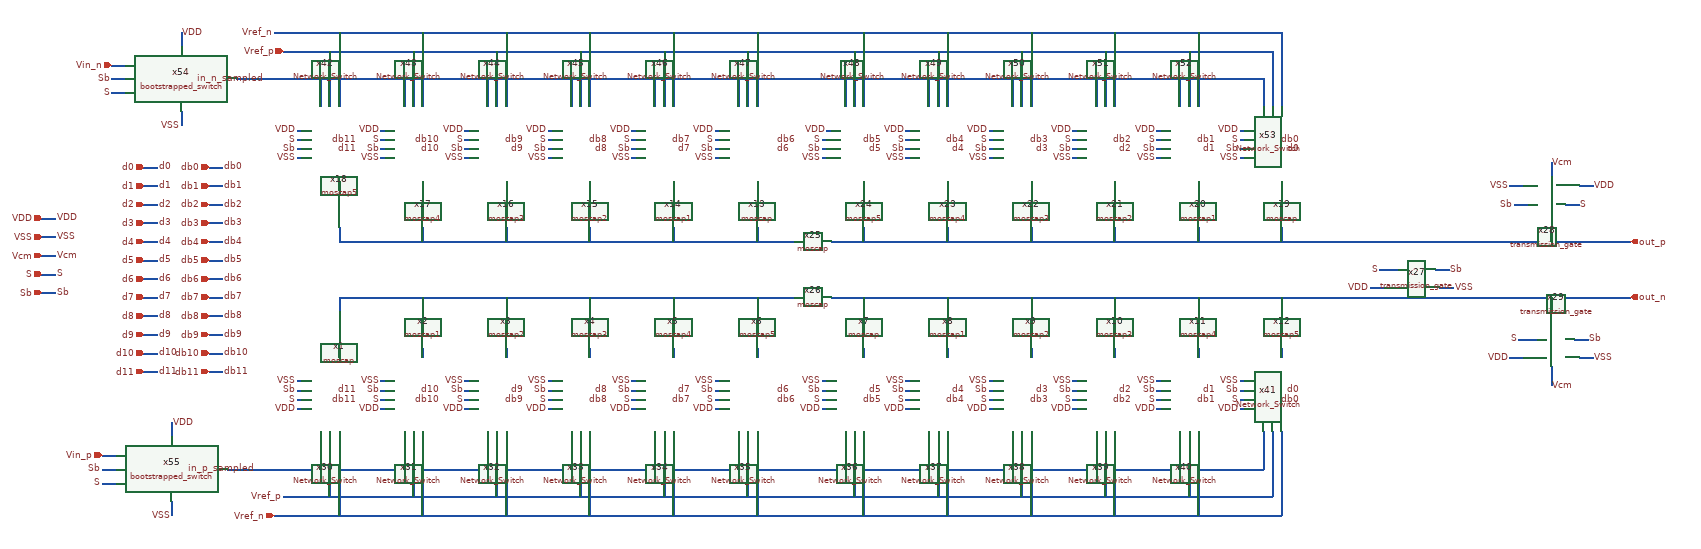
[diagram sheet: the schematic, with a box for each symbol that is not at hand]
v {xschem version=3.4.6 file_version=1.2}
G {}
K {}
V {}
S {}
E {}
N -460 -10 -460 20 {lab=#net1}
N -200 -10 520 -10 {lab=#net1}
N 600 -10 1320 -10 {lab=out_n}
N 1570 -10 1570 20 {lab=out_n}
N 1390 -10 1390 20 {lab=out_n}
N 1210 -10 1210 20 {lab=out_n}
N 1030 -10 1030 20 {lab=out_n}
N 850 -10 850 20 {lab=out_n}
N 670 -10 670 20 {lab=out_n}
N 440 -10 440 20 {lab=#net1}
N 260 -10 260 20 {lab=#net1}
N 80 -10 80 20 {lab=#net1}
N -100 -10 -100 20 {lab=#net1}
N -280 -10 -280 20 {lab=#net1}
N -460 -160 -460 -130 {lab=#net2}
N -200 -130 520 -130 {lab=#net2}
N 600 -130 1320 -130 {lab=out_p}
N 1570 -160 1570 -130 {lab=out_p}
N 1390 -160 1390 -130 {lab=out_p}
N 1210 -160 1210 -130 {lab=out_p}
N 1030 -160 1030 -130 {lab=out_p}
N 850 -160 850 -130 {lab=out_p}
N 670 -160 670 -130 {lab=out_p}
N 440 -160 440 -130 {lab=#net2}
N 260 -160 260 -130 {lab=#net2}
N 80 -160 80 -130 {lab=#net2}
N -100 -160 -100 -130 {lab=#net2}
N -280 -160 -280 -130 {lab=#net2}
N 2150 -300 2150 -270 {lab=Vcm}
N 1930 -130 2320 -130 {lab=out_p}
N 2150 -150 2150 -130 {lab=out_p}
N 1930 -10 2320 -10 {lab=out_n}
N 2150 -10 2150 20 {lab=out_n}
N 2180 -210 2210 -210 {lab=S}
N 2070 -210 2100 -210 {lab=Sb}
N 2060 -250 2090 -250 {lab=VSS}
N 2210 -250 2240 -250 {lab=VDD}
N 2200 80 2230 80 {lab=Sb}
N 2080 80 2120 80 {lab=S}
N 2150 140 2150 160 {lab=Vcm}
N 2210 120 2240 120 {lab=VSS}
N 2060 120 2090 120 {lab=VDD}
N 2150 160 2150 180 {lab=Vcm}
N -330 -10 -200 -10 {lab=#net1}
N -460 -10 -330 -10 {lab=#net1}
N 1320 -10 1780 -10 {lab=out_n}
N 1570 100 1570 120 {lab=#net3}
N 1390 100 1390 120 {lab=#net4}
N 1210 100 1210 120 {lab=#net5}
N 1030 100 1030 120 {lab=#net6}
N 850 100 850 120 {lab=#net7}
N 670 100 670 120 {lab=#net8}
N 1320 -130 1780 -130 {lab=out_p}
N -460 100 -460 120 {lab=#net9}
N -280 100 -280 120 {lab=#net10}
N -100 100 -100 120 {lab=#net11}
N 80 100 80 120 {lab=#net12}
N 440 100 440 120 {lab=#net13}
N 260 100 260 120 {lab=#net14}
N -460 -130 -200 -130 {lab=#net2}
N 1570 -260 1570 -240 {lab=#net15}
N 1390 -260 1390 -240 {lab=#net16}
N 1210 -260 1210 -240 {lab=#net17}
N 1030 -260 1030 -240 {lab=#net18}
N 850 -260 850 -240 {lab=#net19}
N 670 -260 670 -240 {lab=#net20}
N 440 -260 440 -240 {lab=#net21}
N 260 -260 260 -240 {lab=#net22}
N 80 -260 80 -240 {lab=#net23}
N -100 -260 -100 -240 {lab=#net24}
N -280 -260 -280 -240 {lab=#net25}
N -460 -260 -460 -240 {lab=#net26}
N -610 -480 -500 -480 {lab=in_n_sampled}
N -500 -480 -500 -420 {lab=in_n_sampled}
N -500 -480 1530 -480 {lab=in_n_sampled}
N 1530 -480 1530 -420 {lab=in_n_sampled}
N 1350 -480 1350 -420 {lab=in_n_sampled}
N 1170 -480 1170 -420 {lab=in_n_sampled}
N 990 -480 990 -420 {lab=in_n_sampled}
N 810 -480 810 -420 {lab=in_n_sampled}
N 630 -480 630 -420 {lab=in_n_sampled}
N -320 -480 -320 -420 {lab=in_n_sampled}
N -140 -480 -140 -420 {lab=in_n_sampled}
N 40 -480 40 -420 {lab=in_n_sampled}
N 220 -480 220 -420 {lab=in_n_sampled}
N 400 -480 400 -420 {lab=in_n_sampled}
N -600 360 1530 360 {lab=in_p_sampled}
N 1530 280 1530 360 {lab=in_p_sampled}
N 1350 280 1350 360 {lab=in_p_sampled}
N 1170 280 1170 360 {lab=in_p_sampled}
N 990 280 990 360 {lab=in_p_sampled}
N 810 280 810 360 {lab=in_p_sampled}
N 630 280 630 360 {lab=in_p_sampled}
N 400 280 400 360 {lab=in_p_sampled}
N 220 280 220 360 {lab=in_p_sampled}
N 40 280 40 360 {lab=in_p_sampled}
N -140 280 -140 360 {lab=in_p_sampled}
N -320 280 -320 360 {lab=in_p_sampled}
N -500 280 -500 360 {lab=in_p_sampled}
N -1100 -140 -1070 -140 {lab=VSS}
N -1100 -180 -1070 -180 {lab=VDD}
N -1100 -60 -1070 -60 {lab=S}
N -1100 -20 -1070 -20 {lab=Sb}
N -880 -170 -850 -170 {lab=d3}
N -740 -170 -710 -170 {lab=db3}
N -1100 -100 -1070 -100 {lab=Vcm}
N -800 -580 -800 -550 {lab=VDD}
N -820 260 -820 290 {lab=VDD}
N -550 -370 -540 -370 {lab=VDD}
N -370 -370 -360 -370 {lab=VDD}
N -190 -370 -180 -370 {lab=VDD}
N -10 -370 0 -370 {lab=VDD}
N 170 -370 180 -370 {lab=VDD}
N 350 -370 360 -370 {lab=VDD}
N 590 -370 600 -370 {lab=VDD}
N 760 -370 770 -370 {lab=VDD}
N 940 -370 950 -370 {lab=VDD}
N 1120 -370 1130 -370 {lab=VDD}
N 1300 -370 1310 -370 {lab=VDD}
N 1480 -370 1490 -370 {lab=VDD}
N -550 230 -540 230 {lab=VDD}
N -370 230 -360 230 {lab=VDD}
N -190 230 -180 230 {lab=VDD}
N -10 230 0 230 {lab=VDD}
N 170 230 180 230 {lab=VDD}
N 350 230 360 230 {lab=VDD}
N 580 230 590 230 {lab=VDD}
N 760 230 770 230 {lab=VDD}
N 940 230 950 230 {lab=VDD}
N 1300 230 1310 230 {lab=VDD}
N 1120 230 1130 230 {lab=VDD}
N 1480 230 1490 230 {lab=VDD}
N -800 -410 -800 -380 {lab=VSS}
N -820 430 -820 460 {lab=VSS}
N -550 170 -540 170 {lab=VSS}
N -370 170 -360 170 {lab=VSS}
N -190 170 -180 170 {lab=VSS}
N -10 170 0 170 {lab=VSS}
N 170 170 180 170 {lab=VSS}
N 350 170 360 170 {lab=VSS}
N 580 170 590 170 {lab=VSS}
N 760 170 770 170 {lab=VSS}
N 940 170 950 170 {lab=VSS}
N 1120 170 1130 170 {lab=VSS}
N 1300 170 1310 170 {lab=VSS}
N 1480 170 1490 170 {lab=VSS}
N -550 -310 -540 -310 {lab=VSS}
N -370 -310 -360 -310 {lab=VSS}
N -190 -310 -180 -310 {lab=VSS}
N -10 -310 0 -310 {lab=VSS}
N 170 -310 180 -310 {lab=VSS}
N 350 -310 360 -310 {lab=VSS}
N 580 -310 590 -310 {lab=VSS}
N 760 -310 770 -310 {lab=VSS}
N 940 -310 950 -310 {lab=VSS}
N 1120 -310 1130 -310 {lab=VSS}
N 1300 -310 1310 -310 {lab=VSS}
N 1480 -310 1490 -310 {lab=VSS}
N -680 -480 -610 -480 {lab=in_n_sampled}
N -700 360 -600 360 {lab=in_p_sampled}
N -580 -540 1550 -540 {lab=Vref_p}
N 1550 -540 1550 -420 {lab=Vref_p}
N 1570 -580 1570 -420 {lab=Vref_n}
N -600 -580 1570 -580 {lab=Vref_n}
N -480 -540 -480 -420 {lab=Vref_p}
N -460 -580 -460 -420 {lab=Vref_n}
N -300 -540 -300 -420 {lab=Vref_p}
N -280 -580 -280 -420 {lab=Vref_n}
N -120 -540 -120 -420 {lab=Vref_p}
N -100 -580 -100 -420 {lab=Vref_n}
N 60 -540 60 -420 {lab=Vref_p}
N 80 -580 80 -420 {lab=Vref_n}
N 240 -540 240 -420 {lab=Vref_p}
N 260 -580 260 -420 {lab=Vref_n}
N 420 -540 420 -420 {lab=Vref_p}
N 440 -580 440 -420 {lab=Vref_n}
N 650 -540 650 -420 {lab=Vref_p}
N 670 -580 670 -420 {lab=Vref_n}
N 830 -540 830 -420 {lab=Vref_p}
N 850 -580 850 -420 {lab=Vref_n}
N 1010 -540 1010 -420 {lab=Vref_p}
N 1030 -580 1030 -420 {lab=Vref_n}
N 1190 -540 1190 -420 {lab=Vref_p}
N 1210 -580 1210 -420 {lab=Vref_n}
N 1370 -540 1370 -420 {lab=Vref_p}
N 1390 -580 1390 -420 {lab=Vref_n}
N 1550 280 1550 420 {lab=Vref_p}
N -580 420 1550 420 {lab=Vref_p}
N 1570 280 1570 460 {lab=Vref_n}
N -600 460 1570 460 {lab=Vref_n}
N -480 280 -480 420 {lab=Vref_p}
N -460 280 -460 460 {lab=Vref_n}
N -300 280 -300 420 {lab=Vref_p}
N -280 280 -280 460 {lab=Vref_n}
N -120 280 -120 420 {lab=Vref_p}
N -100 280 -100 460 {lab=Vref_n}
N 60 280 60 420 {lab=Vref_p}
N 80 280 80 460 {lab=Vref_n}
N 240 280 240 420 {lab=Vref_p}
N 260 280 260 460 {lab=Vref_n}
N 420 280 420 420 {lab=Vref_p}
N 440 280 440 460 {lab=Vref_n}
N 650 280 650 420 {lab=Vref_p}
N 670 280 670 460 {lab=Vref_n}
N 830 280 830 420 {lab=Vref_p}
N 850 280 850 460 {lab=Vref_n}
N 1010 280 1010 420 {lab=Vref_p}
N 1030 280 1030 460 {lab=Vref_n}
N 1190 280 1190 420 {lab=Vref_p}
N 1210 280 1210 460 {lab=Vref_n}
N 1370 280 1370 420 {lab=Vref_p}
N 1390 280 1390 460 {lab=Vref_n}
N -880 -290 -850 -290 {lab=d0}
N -740 -290 -710 -290 {lab=db0}
N -880 -250 -850 -250 {lab=d1}
N -740 -250 -710 -250 {lab=db1}
N -880 -210 -850 -210 {lab=d2}
N -740 -210 -710 -210 {lab=db2}
N -880 -90 -850 -90 {lab=d5}
N -740 -90 -710 -90 {lab=db5}
N -880 -130 -850 -130 {lab=d4}
N -740 -130 -710 -130 {lab=db4}
N -880 -10 -850 -10 {lab=d7}
N -740 -10 -710 -10 {lab=db7}
N -880 -50 -850 -50 {lab=d6}
N -740 -50 -710 -50 {lab=db6}
N -880 70 -850 70 {lab=d9}
N -740 70 -710 70 {lab=db9}
N -880 30 -850 30 {lab=d8}
N -740 30 -710 30 {lab=db8}
N -880 150 -850 150 {lab=d11}
N -740 150 -710 150 {lab=db11}
N -880 110 -850 110 {lab=d10}
N -740 110 -710 110 {lab=db10}
N -550 -350 -540 -350 {lab=S}
N -550 -330 -540 -330 {lab=Sb}
N -370 -350 -360 -350 {lab=S}
N -370 -330 -360 -330 {lab=Sb}
N -190 -350 -180 -350 {lab=S}
N -190 -330 -180 -330 {lab=Sb}
N -10 -350 0 -350 {lab=S}
N -10 -330 0 -330 {lab=Sb}
N 170 -350 180 -350 {lab=S}
N 170 -330 180 -330 {lab=Sb}
N 350 -350 360 -350 {lab=S}
N 350 -330 360 -330 {lab=Sb}
N 580 -350 590 -350 {lab=S}
N 580 -330 590 -330 {lab=Sb}
N 760 -350 770 -350 {lab=S}
N 760 -330 770 -330 {lab=Sb}
N 940 -350 950 -350 {lab=S}
N 940 -330 950 -330 {lab=Sb}
N 1120 -350 1130 -350 {lab=S}
N 1120 -330 1130 -330 {lab=Sb}
N 1300 -350 1310 -350 {lab=S}
N 1300 -330 1310 -330 {lab=Sb}
N 1480 -350 1490 -350 {lab=S}
N 1480 -330 1490 -330 {lab=Sb}
N -550 210 -540 210 {lab=S}
N -550 190 -540 190 {lab=Sb}
N -370 210 -360 210 {lab=S}
N -370 190 -360 190 {lab=Sb}
N -190 210 -180 210 {lab=S}
N -190 190 -180 190 {lab=Sb}
N -10 210 0 210 {lab=S}
N -10 190 0 190 {lab=Sb}
N 170 210 180 210 {lab=S}
N 170 190 180 190 {lab=Sb}
N 350 210 360 210 {lab=S}
N 350 190 360 190 {lab=Sb}
N 580 210 590 210 {lab=S}
N 580 190 590 190 {lab=Sb}
N 760 210 770 210 {lab=S}
N 760 190 770 190 {lab=Sb}
N 940 210 950 210 {lab=S}
N 940 190 950 190 {lab=Sb}
N 1120 210 1130 210 {lab=S}
N 1120 190 1130 190 {lab=Sb}
N 1300 210 1310 210 {lab=S}
N 1300 190 1310 190 {lab=Sb}
N 1480 210 1490 210 {lab=S}
N 1480 190 1490 190 {lab=Sb}
N -950 -510 -920 -510 {lab=Vin_n}
N -970 330 -940 330 {lab=Vin_p}
N -950 -450 -920 -450 {lab=S}
N -950 -480 -920 -480 {lab=Sb}
N -970 390 -940 390 {lab=S}
N -970 360 -940 360 {lab=Sb}
N 1780 -130 1930 -130 {lab=out_p}
N 1780 -10 1930 -10 {lab=out_n}
N 1900 -70 1930 -70 {lab=Sb}
N 1780 -70 1820 -70 {lab=S}
N 1910 -30 1940 -30 {lab=VSS}
N 1760 -30 1790 -30 {lab=VDD}
C {project/CAP/moscap.sym} -460 60 0 0 {name=x1}
C {project/CAP/moscap1.sym} -280 80 0 0 {name=x2}
C {project/CAP/moscap2.sym} -100 60 0 0 {name=x3}
C {project/CAP/moscap3.sym} 80 60 0 0 {name=x4}
C {project/CAP/moscap4.sym} 260 60 0 0 {name=x5}
C {project/CAP/moscap5.sym} 440 60 0 0 {name=x6}
C {project/CAP/moscap.sym} 670 60 0 0 {name=x7}
C {project/CAP/moscap1.sym} 850 80 0 0 {name=x8}
C {project/CAP/moscap2.sym} 1030 60 0 0 {name=x9}
C {project/CAP/moscap3.sym} 1210 60 0 0 {name=x10}
C {project/CAP/moscap4.sym} 1390 60 0 0 {name=x11}
C {project/CAP/moscap5.sym} 1570 60 0 0 {name=x12}
C {project/CAP/moscap.sym} 440 -200 2 0 {name=x13}
C {project/CAP/moscap1.sym} 260 -220 2 0 {name=x14}
C {project/CAP/moscap2.sym} 80 -200 2 0 {name=x15}
C {project/CAP/moscap3.sym} -100 -200 2 0 {name=x16}
C {project/CAP/moscap4.sym} -280 -200 2 0 {name=x17}
C {project/CAP/moscap5.sym} -460 -200 2 0 {name=x18}
C {project/CAP/moscap.sym} 1570 -200 2 0 {name=x19}
C {project/CAP/moscap1.sym} 1390 -220 2 0 {name=x20}
C {project/CAP/moscap2.sym} 1210 -200 2 0 {name=x21}
C {project/CAP/moscap3.sym} 1030 -200 2 0 {name=x22}
C {project/CAP/moscap4.sym} 850 -200 2 0 {name=x23}
C {project/CAP/moscap5.sym} 670 -200 2 0 {name=x24}
C {project/CAP/moscap.sym} 560 -130 3 0 {name=x25}
C {project/CAP/moscap.sym} 560 -10 3 0 {name=x26}
C {project/transmission_gate.sym} 2150 -200 1 0 {name=x28}
C {project/transmission_gate.sym} 2150 70 3 0 {name=x29}
C {project/Network_Switch.sym} -480 200 2 1 {name=x30}
C {project/Network_Switch.sym} -300 200 2 1 {name=x31}
C {project/Network_Switch.sym} -120 200 2 1 {name=x32}
C {project/Network_Switch.sym} 60 200 2 1 {name=x33}
C {project/Network_Switch.sym} 240 200 2 1 {name=x34}
C {project/Network_Switch.sym} 420 200 2 1 {name=x35}
C {project/Network_Switch.sym} 650 200 2 1 {name=x36}
C {project/Network_Switch.sym} 830 200 2 1 {name=x37}
C {project/Network_Switch.sym} 1010 200 2 1 {name=x38}
C {project/Network_Switch.sym} 1190 200 2 1 {name=x39}
C {project/Network_Switch.sym} 1370 200 2 1 {name=x40}
C {project/Network_Switch.sym} 1550 200 2 1 {name=x41}
C {project/Network_Switch.sym} -480 -340 0 0 {name=x42}
C {project/Network_Switch.sym} -300 -340 0 0 {name=x43}
C {project/Network_Switch.sym} -120 -340 0 0 {name=x44}
C {project/Network_Switch.sym} 60 -340 0 0 {name=x45}
C {project/Network_Switch.sym} 240 -340 0 0 {name=x46}
C {project/Network_Switch.sym} 420 -340 0 0 {name=x47}
C {project/Network_Switch.sym} 650 -340 0 0 {name=x48}
C {project/Network_Switch.sym} 830 -340 0 0 {name=x49}
C {project/Network_Switch.sym} 1010 -340 0 0 {name=x50}
C {project/Network_Switch.sym} 1190 -340 0 0 {name=x51}
C {project/Network_Switch.sym} 1370 -340 0 0 {name=x52}
C {project/Network_Switch.sym} 1550 -340 0 0 {name=x53}
C {project/bootstrapped_switch.sym} -800 -480 0 0 {name=x54}
C {project/bootstrapped_switch.sym} -820 360 0 0 {name=x55}
C {devices/ipin.sym} -1100 -180 0 0 {name=p5 lab=VDD}
C {devices/ipin.sym} -1100 -140 0 0 {name=p6 lab=VSS}
C {devices/ipin.sym} -1100 -60 0 0 {name=p7 lab=S}
C {devices/lab_pin.sym} -1070 -180 2 0 {name=p8 sig_type=std_logic lab=VDD}
C {devices/lab_pin.sym} -1070 -140 2 0 {name=p9 sig_type=std_logic lab=VSS}
C {devices/ipin.sym} -1100 -20 0 0 {name=p18 lab=Sb}
C {devices/ipin.sym} -880 -170 0 0 {name=p19 lab=d3}
C {devices/ipin.sym} -740 -170 0 0 {name=p20 lab=db3}
C {devices/lab_pin.sym} -1070 -60 2 0 {name=p21 sig_type=std_logic lab=S}
C {devices/lab_pin.sym} -1070 -20 2 0 {name=p22 sig_type=std_logic lab=Sb}
C {devices/lab_pin.sym} -850 -170 2 0 {name=p27 sig_type=std_logic lab=d3}
C {devices/lab_pin.sym} -710 -170 2 0 {name=p28 sig_type=std_logic lab=db3}
C {devices/ipin.sym} -1100 -100 0 0 {name=p1 lab=Vcm}
C {devices/lab_pin.sym} -1070 -100 2 0 {name=p2 sig_type=std_logic lab=Vcm}
C {devices/lab_pin.sym} -800 -580 2 0 {name=p3 sig_type=std_logic lab=VDD}
C {devices/lab_pin.sym} -820 260 2 0 {name=p4 sig_type=std_logic lab=VDD}
C {devices/lab_pin.sym} -550 -370 0 0 {name=p10 sig_type=std_logic lab=VDD}
C {devices/lab_pin.sym} -370 -370 0 0 {name=p11 sig_type=std_logic lab=VDD}
C {devices/lab_pin.sym} -190 -370 0 0 {name=p12 sig_type=std_logic lab=VDD}
C {devices/lab_pin.sym} -10 -370 0 0 {name=p13 sig_type=std_logic lab=VDD}
C {devices/lab_pin.sym} 170 -370 0 0 {name=p14 sig_type=std_logic lab=VDD}
C {devices/lab_pin.sym} 350 -370 0 0 {name=p15 sig_type=std_logic lab=VDD}
C {devices/lab_pin.sym} 590 -370 0 0 {name=p16 sig_type=std_logic lab=VDD}
C {devices/lab_pin.sym} 760 -370 0 0 {name=p17 sig_type=std_logic lab=VDD}
C {devices/lab_pin.sym} 940 -370 0 0 {name=p23 sig_type=std_logic lab=VDD}
C {devices/lab_pin.sym} 1120 -370 0 0 {name=p24 sig_type=std_logic lab=VDD}
C {devices/lab_pin.sym} 1300 -370 0 0 {name=p25 sig_type=std_logic lab=VDD}
C {devices/lab_pin.sym} 1480 -370 0 0 {name=p26 sig_type=std_logic lab=VDD}
C {devices/lab_pin.sym} -550 230 0 0 {name=p29 sig_type=std_logic lab=VDD}
C {devices/lab_pin.sym} -370 230 0 0 {name=p30 sig_type=std_logic lab=VDD}
C {devices/lab_pin.sym} -190 230 0 0 {name=p31 sig_type=std_logic lab=VDD}
C {devices/lab_pin.sym} -10 230 0 0 {name=p32 sig_type=std_logic lab=VDD}
C {devices/lab_pin.sym} 170 230 0 0 {name=p33 sig_type=std_logic lab=VDD}
C {devices/lab_pin.sym} 350 230 0 0 {name=p34 sig_type=std_logic lab=VDD}
C {devices/lab_pin.sym} 580 230 0 0 {name=p35 sig_type=std_logic lab=VDD}
C {devices/lab_pin.sym} 760 230 0 0 {name=p36 sig_type=std_logic lab=VDD}
C {devices/lab_pin.sym} 940 230 0 0 {name=p37 sig_type=std_logic lab=VDD}
C {devices/lab_pin.sym} 1300 230 0 0 {name=p38 sig_type=std_logic lab=VDD}
C {devices/lab_pin.sym} 1120 230 0 0 {name=p39 sig_type=std_logic lab=VDD}
C {devices/lab_pin.sym} 1480 230 0 0 {name=p40 sig_type=std_logic lab=VDD}
C {devices/lab_pin.sym} 2060 120 0 0 {name=p41 sig_type=std_logic lab=VDD}
C {devices/lab_pin.sym} 2240 -250 2 0 {name=p43 sig_type=std_logic lab=VDD}
C {devices/lab_pin.sym} -800 -380 0 0 {name=p44 sig_type=std_logic lab=VSS}
C {devices/lab_pin.sym} -820 460 0 0 {name=p45 sig_type=std_logic lab=VSS}
C {devices/lab_pin.sym} -550 170 0 0 {name=p46 sig_type=std_logic lab=VSS}
C {devices/lab_pin.sym} -370 170 0 0 {name=p47 sig_type=std_logic lab=VSS}
C {devices/lab_pin.sym} -190 170 0 0 {name=p48 sig_type=std_logic lab=VSS}
C {devices/lab_pin.sym} -10 170 0 0 {name=p49 sig_type=std_logic lab=VSS}
C {devices/lab_pin.sym} 170 170 0 0 {name=p50 sig_type=std_logic lab=VSS}
C {devices/lab_pin.sym} 350 170 0 0 {name=p51 sig_type=std_logic lab=VSS}
C {devices/lab_pin.sym} 580 170 0 0 {name=p52 sig_type=std_logic lab=VSS}
C {devices/lab_pin.sym} 760 170 0 0 {name=p53 sig_type=std_logic lab=VSS}
C {devices/lab_pin.sym} 940 170 0 0 {name=p54 sig_type=std_logic lab=VSS}
C {devices/lab_pin.sym} 1120 170 0 0 {name=p55 sig_type=std_logic lab=VSS}
C {devices/lab_pin.sym} 1300 170 0 0 {name=p56 sig_type=std_logic lab=VSS}
C {devices/lab_pin.sym} 1480 170 0 0 {name=p57 sig_type=std_logic lab=VSS}
C {devices/lab_pin.sym} -550 -310 0 0 {name=p58 sig_type=std_logic lab=VSS}
C {devices/lab_pin.sym} -370 -310 0 0 {name=p59 sig_type=std_logic lab=VSS}
C {devices/lab_pin.sym} -190 -310 0 0 {name=p60 sig_type=std_logic lab=VSS}
C {devices/lab_pin.sym} -10 -310 0 0 {name=p61 sig_type=std_logic lab=VSS}
C {devices/lab_pin.sym} 170 -310 0 0 {name=p62 sig_type=std_logic lab=VSS}
C {devices/lab_pin.sym} 350 -310 0 0 {name=p63 sig_type=std_logic lab=VSS}
C {devices/lab_pin.sym} 580 -310 0 0 {name=p64 sig_type=std_logic lab=VSS}
C {devices/lab_pin.sym} 760 -310 0 0 {name=p65 sig_type=std_logic lab=VSS}
C {devices/lab_pin.sym} 940 -310 0 0 {name=p66 sig_type=std_logic lab=VSS}
C {devices/lab_pin.sym} 1120 -310 0 0 {name=p67 sig_type=std_logic lab=VSS}
C {devices/lab_pin.sym} 1300 -310 0 0 {name=p68 sig_type=std_logic lab=VSS}
C {devices/lab_pin.sym} 1480 -310 0 0 {name=p69 sig_type=std_logic lab=VSS}
C {devices/lab_pin.sym} 2060 -250 0 0 {name=p72 sig_type=std_logic lab=VSS}
C {devices/lab_pin.sym} 2240 120 2 0 {name=p73 sig_type=std_logic lab=VSS}
C {devices/lab_pin.sym} 2150 -300 2 0 {name=p74 sig_type=std_logic lab=Vcm}
C {devices/lab_pin.sym} 2150 180 2 0 {name=p75 sig_type=std_logic lab=Vcm}
C {devices/opin.sym} 2320 -130 0 0 {name=p76 lab=out_p}
C {devices/opin.sym} 2320 -10 0 0 {name=p77 lab=out_n
}
C {devices/ipin.sym} -580 -540 0 0 {name=p78 lab=Vref_p}
C {devices/ipin.sym} -600 460 0 0 {name=p79 lab=Vref_n}
C {devices/lab_pin.sym} -580 420 0 0 {name=p80 sig_type=std_logic lab=Vref_p}
C {devices/lab_pin.sym} -600 -580 0 0 {name=p81 sig_type=std_logic lab=Vref_n}
C {devices/ipin.sym} -880 -290 0 0 {name=p82 lab=d0}
C {devices/ipin.sym} -740 -290 0 0 {name=p83 lab=db0}
C {devices/lab_pin.sym} -850 -290 2 0 {name=p84 sig_type=std_logic lab=d0}
C {devices/lab_pin.sym} -710 -290 2 0 {name=p85 sig_type=std_logic lab=db0}
C {devices/ipin.sym} -880 -250 0 0 {name=p86 lab=d1}
C {devices/ipin.sym} -740 -250 0 0 {name=p87 lab=db1}
C {devices/lab_pin.sym} -850 -250 2 0 {name=p88 sig_type=std_logic lab=d1}
C {devices/lab_pin.sym} -710 -250 2 0 {name=p89 sig_type=std_logic lab=db1}
C {devices/ipin.sym} -880 -210 0 0 {name=p90 lab=d2}
C {devices/ipin.sym} -740 -210 0 0 {name=p91 lab=db2}
C {devices/lab_pin.sym} -850 -210 2 0 {name=p92 sig_type=std_logic lab=d2}
C {devices/lab_pin.sym} -710 -210 2 0 {name=p93 sig_type=std_logic lab=db2}
C {devices/ipin.sym} -880 -90 0 0 {name=p94 lab=d5}
C {devices/ipin.sym} -740 -90 0 0 {name=p95 lab=db5}
C {devices/lab_pin.sym} -850 -90 2 0 {name=p96 sig_type=std_logic lab=d5}
C {devices/lab_pin.sym} -710 -90 2 0 {name=p97 sig_type=std_logic lab=db5}
C {devices/ipin.sym} -880 -130 0 0 {name=p98 lab=d4}
C {devices/ipin.sym} -740 -130 0 0 {name=p99 lab=db4}
C {devices/lab_pin.sym} -850 -130 2 0 {name=p100 sig_type=std_logic lab=d4}
C {devices/lab_pin.sym} -710 -130 2 0 {name=p101 sig_type=std_logic lab=db4}
C {devices/ipin.sym} -880 -10 0 0 {name=p102 lab=d7}
C {devices/ipin.sym} -740 -10 0 0 {name=p103 lab=db7}
C {devices/lab_pin.sym} -850 -10 2 0 {name=p104 sig_type=std_logic lab=d7}
C {devices/lab_pin.sym} -710 -10 2 0 {name=p105 sig_type=std_logic lab=db7}
C {devices/ipin.sym} -880 -50 0 0 {name=p106 lab=d6}
C {devices/ipin.sym} -740 -50 0 0 {name=p107 lab=db6}
C {devices/lab_pin.sym} -850 -50 2 0 {name=p108 sig_type=std_logic lab=d6}
C {devices/lab_pin.sym} -710 -50 2 0 {name=p109 sig_type=std_logic lab=db6}
C {devices/ipin.sym} -880 70 0 0 {name=p110 lab=d9}
C {devices/ipin.sym} -740 70 0 0 {name=p111 lab=db9}
C {devices/lab_pin.sym} -850 70 2 0 {name=p112 sig_type=std_logic lab=d9}
C {devices/lab_pin.sym} -710 70 2 0 {name=p113 sig_type=std_logic lab=db9}
C {devices/ipin.sym} -880 30 0 0 {name=p114 lab=d8}
C {devices/ipin.sym} -740 30 0 0 {name=p115 lab=db8}
C {devices/lab_pin.sym} -850 30 2 0 {name=p116 sig_type=std_logic lab=d8}
C {devices/lab_pin.sym} -710 30 2 0 {name=p117 sig_type=std_logic lab=db8}
C {devices/ipin.sym} -880 150 0 0 {name=p118 lab=d11}
C {devices/ipin.sym} -740 150 0 0 {name=p119 lab=db11}
C {devices/lab_pin.sym} -850 150 2 0 {name=p120 sig_type=std_logic lab=d11}
C {devices/lab_pin.sym} -710 150 2 0 {name=p121 sig_type=std_logic lab=db11}
C {devices/ipin.sym} -880 110 0 0 {name=p122 lab=d10}
C {devices/ipin.sym} -740 110 0 0 {name=p123 lab=db10}
C {devices/lab_pin.sym} -850 110 2 0 {name=p124 sig_type=std_logic lab=d10}
C {devices/lab_pin.sym} -710 110 2 0 {name=p125 sig_type=std_logic lab=db10}
C {devices/lab_pin.sym} -550 -350 2 1 {name=p126 sig_type=std_logic lab=S}
C {devices/lab_pin.sym} -550 -330 2 1 {name=p127 sig_type=std_logic lab=Sb}
C {devices/lab_pin.sym} -370 -350 2 1 {name=p128 sig_type=std_logic lab=S}
C {devices/lab_pin.sym} -370 -330 2 1 {name=p129 sig_type=std_logic lab=Sb}
C {devices/lab_pin.sym} -190 -350 2 1 {name=p130 sig_type=std_logic lab=S}
C {devices/lab_pin.sym} -190 -330 2 1 {name=p131 sig_type=std_logic lab=Sb}
C {devices/lab_pin.sym} -10 -350 2 1 {name=p132 sig_type=std_logic lab=S}
C {devices/lab_pin.sym} -10 -330 2 1 {name=p133 sig_type=std_logic lab=Sb}
C {devices/lab_pin.sym} 170 -350 2 1 {name=p134 sig_type=std_logic lab=S}
C {devices/lab_pin.sym} 170 -330 2 1 {name=p135 sig_type=std_logic lab=Sb}
C {devices/lab_pin.sym} 350 -350 2 1 {name=p136 sig_type=std_logic lab=S}
C {devices/lab_pin.sym} 350 -330 2 1 {name=p137 sig_type=std_logic lab=Sb}
C {devices/lab_pin.sym} 580 -350 2 1 {name=p138 sig_type=std_logic lab=S}
C {devices/lab_pin.sym} 580 -330 2 1 {name=p139 sig_type=std_logic lab=Sb}
C {devices/lab_pin.sym} 760 -350 2 1 {name=p140 sig_type=std_logic lab=S}
C {devices/lab_pin.sym} 760 -330 2 1 {name=p141 sig_type=std_logic lab=Sb}
C {devices/lab_pin.sym} 940 -350 2 1 {name=p142 sig_type=std_logic lab=S}
C {devices/lab_pin.sym} 940 -330 2 1 {name=p143 sig_type=std_logic lab=Sb}
C {devices/lab_pin.sym} 1120 -350 2 1 {name=p144 sig_type=std_logic lab=S}
C {devices/lab_pin.sym} 1120 -330 2 1 {name=p145 sig_type=std_logic lab=Sb}
C {devices/lab_pin.sym} 1300 -350 2 1 {name=p146 sig_type=std_logic lab=S}
C {devices/lab_pin.sym} 1300 -330 2 1 {name=p147 sig_type=std_logic lab=Sb}
C {devices/lab_pin.sym} 1480 -350 2 1 {name=p148 sig_type=std_logic lab=S}
C {devices/lab_pin.sym} 1480 -330 2 1 {name=p149 sig_type=std_logic lab=Sb}
C {devices/lab_pin.sym} -550 210 2 1 {name=p152 sig_type=std_logic lab=S}
C {devices/lab_pin.sym} -550 190 2 1 {name=p153 sig_type=std_logic lab=Sb}
C {devices/lab_pin.sym} -370 210 2 1 {name=p150 sig_type=std_logic lab=S}
C {devices/lab_pin.sym} -370 190 2 1 {name=p151 sig_type=std_logic lab=Sb}
C {devices/lab_pin.sym} -190 210 2 1 {name=p154 sig_type=std_logic lab=S}
C {devices/lab_pin.sym} -190 190 2 1 {name=p155 sig_type=std_logic lab=Sb}
C {devices/lab_pin.sym} -10 210 2 1 {name=p156 sig_type=std_logic lab=S}
C {devices/lab_pin.sym} -10 190 2 1 {name=p157 sig_type=std_logic lab=Sb}
C {devices/lab_pin.sym} 170 210 2 1 {name=p158 sig_type=std_logic lab=S}
C {devices/lab_pin.sym} 170 190 2 1 {name=p159 sig_type=std_logic lab=Sb}
C {devices/lab_pin.sym} 350 210 2 1 {name=p160 sig_type=std_logic lab=S}
C {devices/lab_pin.sym} 350 190 2 1 {name=p161 sig_type=std_logic lab=Sb}
C {devices/lab_pin.sym} 580 210 2 1 {name=p162 sig_type=std_logic lab=S}
C {devices/lab_pin.sym} 580 190 2 1 {name=p163 sig_type=std_logic lab=Sb}
C {devices/lab_pin.sym} 760 210 2 1 {name=p164 sig_type=std_logic lab=S}
C {devices/lab_pin.sym} 760 190 2 1 {name=p165 sig_type=std_logic lab=Sb}
C {devices/lab_pin.sym} 940 210 2 1 {name=p166 sig_type=std_logic lab=S}
C {devices/lab_pin.sym} 940 190 2 1 {name=p167 sig_type=std_logic lab=Sb}
C {devices/lab_pin.sym} 1120 210 2 1 {name=p168 sig_type=std_logic lab=S}
C {devices/lab_pin.sym} 1120 190 2 1 {name=p169 sig_type=std_logic lab=Sb}
C {devices/lab_pin.sym} 1300 210 2 1 {name=p170 sig_type=std_logic lab=S}
C {devices/lab_pin.sym} 1300 190 2 1 {name=p171 sig_type=std_logic lab=Sb}
C {devices/lab_pin.sym} 1480 210 2 1 {name=p172 sig_type=std_logic lab=S}
C {devices/lab_pin.sym} 1480 190 2 1 {name=p173 sig_type=std_logic lab=Sb}
C {devices/lab_pin.sym} -420 -330 0 0 {name=p174 sig_type=std_logic lab=d11}
C {devices/lab_pin.sym} -420 -350 0 0 {name=p175 sig_type=std_logic lab=db11}
C {devices/lab_pin.sym} -240 -330 0 0 {name=p176 sig_type=std_logic lab=d10}
C {devices/lab_pin.sym} -240 -350 0 0 {name=p177 sig_type=std_logic lab=db10}
C {devices/lab_pin.sym} -60 -330 0 0 {name=p178 sig_type=std_logic lab=d9}
C {devices/lab_pin.sym} -60 -350 0 0 {name=p179 sig_type=std_logic lab=db9}
C {devices/lab_pin.sym} -420 210 0 0 {name=p180 sig_type=std_logic lab=db11}
C {devices/lab_pin.sym} -420 190 0 0 {name=p181 sig_type=std_logic lab=d11}
C {devices/lab_pin.sym} -240 210 0 0 {name=p182 sig_type=std_logic lab=db10}
C {devices/lab_pin.sym} -240 190 0 0 {name=p183 sig_type=std_logic lab=d10}
C {devices/lab_pin.sym} -60 210 0 0 {name=p184 sig_type=std_logic lab=db9}
C {devices/lab_pin.sym} -60 190 0 0 {name=p185 sig_type=std_logic lab=d9}
C {devices/lab_pin.sym} 120 -330 0 0 {name=p186 sig_type=std_logic lab=d8}
C {devices/lab_pin.sym} 120 190 0 0 {name=p187 sig_type=std_logic lab=d8}
C {devices/lab_pin.sym} 120 -350 0 0 {name=p188 sig_type=std_logic lab=db8}
C {devices/lab_pin.sym} 120 210 0 0 {name=p189 sig_type=std_logic lab=db8}
C {devices/lab_pin.sym} 300 -330 0 0 {name=p190 sig_type=std_logic lab=d7}
C {devices/lab_pin.sym} 300 190 0 0 {name=p191 sig_type=std_logic lab=d7}
C {devices/lab_pin.sym} 300 -350 0 0 {name=p192 sig_type=std_logic lab=db7}
C {devices/lab_pin.sym} 300 210 0 0 {name=p193 sig_type=std_logic lab=db7}
C {devices/lab_pin.sym} 480 -330 2 0 {name=p194 sig_type=std_logic lab=d6}
C {devices/lab_pin.sym} 480 190 2 0 {name=p195 sig_type=std_logic lab=d6}
C {devices/lab_pin.sym} 480 -350 2 0 {name=p196 sig_type=std_logic lab=db6}
C {devices/lab_pin.sym} 480 210 2 0 {name=p197 sig_type=std_logic lab=db6}
C {devices/lab_pin.sym} 710 -330 0 0 {name=p198 sig_type=std_logic lab=d5}
C {devices/lab_pin.sym} 710 190 0 0 {name=p199 sig_type=std_logic lab=d5}
C {devices/lab_pin.sym} 710 -350 0 0 {name=p200 sig_type=std_logic lab=db5}
C {devices/lab_pin.sym} 710 210 0 0 {name=p201 sig_type=std_logic lab=db5}
C {devices/lab_pin.sym} 890 -330 0 0 {name=p202 sig_type=std_logic lab=d4}
C {devices/lab_pin.sym} 890 -350 0 0 {name=p203 sig_type=std_logic lab=db4}
C {devices/lab_pin.sym} 890 210 0 0 {name=p204 sig_type=std_logic lab=db4}
C {devices/lab_pin.sym} 890 190 0 0 {name=p205 sig_type=std_logic lab=d4}
C {devices/lab_pin.sym} 1070 190 0 0 {name=p206 sig_type=std_logic lab=d3}
C {devices/lab_pin.sym} 1070 210 0 0 {name=p207 sig_type=std_logic lab=db3}
C {devices/lab_pin.sym} 1070 -350 0 0 {name=p208 sig_type=std_logic lab=db3}
C {devices/lab_pin.sym} 1070 -330 0 0 {name=p209 sig_type=std_logic lab=d3}
C {devices/lab_pin.sym} 1250 -330 0 0 {name=p210 sig_type=std_logic lab=d2}
C {devices/lab_pin.sym} 1250 -350 0 0 {name=p211 sig_type=std_logic lab=db2}
C {devices/lab_pin.sym} 1250 210 0 0 {name=p212 sig_type=std_logic lab=db2}
C {devices/lab_pin.sym} 1250 190 0 0 {name=p213 sig_type=std_logic lab=d2}
C {devices/lab_pin.sym} 1430 190 0 0 {name=p214 sig_type=std_logic lab=d1}
C {devices/lab_pin.sym} 1430 210 0 0 {name=p215 sig_type=std_logic lab=db1}
C {devices/lab_pin.sym} 1430 -350 0 0 {name=p216 sig_type=std_logic lab=db1}
C {devices/lab_pin.sym} 1430 -330 0 0 {name=p217 sig_type=std_logic lab=d1}
C {devices/lab_pin.sym} 1610 -330 0 0 {name=p218 sig_type=std_logic lab=d0}
C {devices/lab_pin.sym} 1610 190 0 0 {name=p219 sig_type=std_logic lab=d0}
C {devices/lab_pin.sym} 1610 -350 0 0 {name=p220 sig_type=std_logic lab=db0}
C {devices/lab_pin.sym} 1610 210 0 0 {name=p221 sig_type=std_logic lab=db0}
C {devices/lab_pin.sym} 2210 -210 2 0 {name=p222 sig_type=std_logic lab=S}
C {devices/lab_pin.sym} 2080 80 0 0 {name=p223 sig_type=std_logic lab=S}
C {devices/lab_pin.sym} 2070 -210 0 0 {name=p225 sig_type=std_logic lab=Sb}
C {devices/lab_pin.sym} 2230 80 2 0 {name=p226 sig_type=std_logic lab=Sb}
C {devices/ipin.sym} -950 -510 0 0 {name=p227 lab=Vin_n}
C {devices/ipin.sym} -970 330 0 0 {name=p228 lab=Vin_p}
C {devices/lab_pin.sym} -950 -450 0 0 {name=p229 sig_type=std_logic lab=S}
C {devices/lab_pin.sym} -950 -480 0 0 {name=p230 sig_type=std_logic lab=Sb}
C {devices/lab_pin.sym} -970 390 0 0 {name=p231 sig_type=std_logic lab=S}
C {devices/lab_pin.sym} -970 360 0 0 {name=p232 sig_type=std_logic lab=Sb}
C {devices/lab_pin.sym} -620 -480 3 0 {name=p233 sig_type=std_logic lab=in_n_sampled}
C {devices/lab_pin.sym} -640 360 1 0 {name=p234 sig_type=std_logic lab=in_p_sampled}
C {project/transmission_gate.sym} 1850 -80 3 0 {name=x27}
C {devices/lab_pin.sym} 1760 -30 0 0 {name=p42 sig_type=std_logic lab=VDD}
C {devices/lab_pin.sym} 1940 -30 2 0 {name=p70 sig_type=std_logic lab=VSS}
C {devices/lab_pin.sym} 1780 -70 0 0 {name=p71 sig_type=std_logic lab=S}
C {devices/lab_pin.sym} 1930 -70 2 0 {name=p224 sig_type=std_logic lab=Sb}
